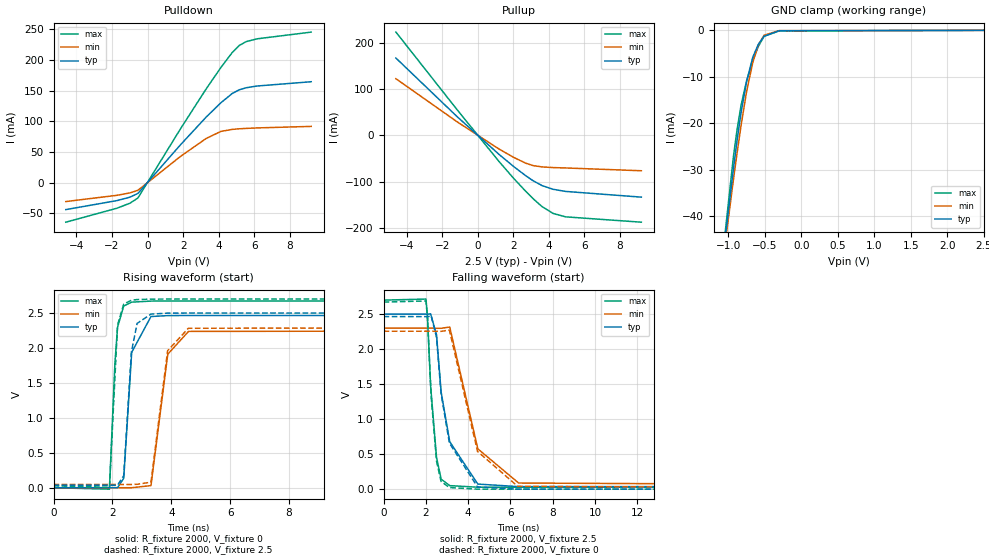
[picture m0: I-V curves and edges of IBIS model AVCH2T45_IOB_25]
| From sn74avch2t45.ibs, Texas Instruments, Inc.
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[Model]   AVCH2T45_IOB_25
Model_type  I/O
Vinl=0.7
Vinh=1.6
Enable   Active-High
Vref =   0
Rref =   2000
Cref =   15p
Vmeas =   1.25
| variable   typ   min   max
C_comp   5.05pF   4.26pF   5.75pF
| C_pullup   4.25pF   3.21pF   5.63pF
| C_pulldown   4.37pF   3.83pF   4.80pF
| C_tri-state   5.05pF   4.26pF   5.75pF
[Temperature Range]   40   100   -40
| Ambient temperature   25   85   -40
[Voltage range]   2.5   2.3   2.7
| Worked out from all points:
|   slope of the pulldown table from 0 to 0.375 V, typ, clamps not added: 29.4 ohm
|   slope of the pullup table from 0 to 0.375 V, typ, clamps not added: 28.8 ohm
|   GND clamp passes 1 mA (typ) near -0.49 V on its own axis
|   rising waveform, R_fixture 2000, V_fixture 0: 20-80 % time 216ps typ, 349ps min, 155ps max; typ from 0 V to 2.46 V
|   falling waveform, R_fixture 2000, V_fixture 2.5: 20-80 % time 733ps typ, 1.05ns min, 341ps max; typ from 2.5 V to 0.036 V
|   rising waveform, R_fixture 2000, V_fixture 2.5: 20-80 % time 214ps typ, 345ps min, 155ps max; typ from 0.036 V to 2.5 V
|   falling waveform, R_fixture 2000, V_fixture 0: 20-80 % time 727ps typ, 1.05ns min, 333ps max; typ from 2.46 V to 0 V
[GND Clamp]
| AVCH2T45_IOB_25
|   Voltage   I(typ)   I(min)   I(max)
-4.6V     -599.7mA   -548.2mA   -664.8mA
-1.105V   -53.1mA    -53.46mA   -52.72mA
-1.08V    -49.64mA   -50.32mA   -48.82mA
-930mV    -29.72mA   -32.1mA    -27.1mA
-880mV    -23.65mA   -26.37mA   -21.29mA
-825mV    -17.62mA   -20.4mA    -16.07mA
-750mV    -11.02mA   -13.17mA   -10.85mA
-665mV    -5.769mA   -6.898mA   -6.554mA
-590mV    -3.043mA   -3.142mA   -3.475mA
-510mV    -1.266mA   -1.045mA   -1.273mA
-305mV    -86.62uA   -60.85uA   -133.1uA
2.5V      1.213nA    2.547uA    -2.967uA
[Pulldown]
| AVCH2T45_IOB_25
|   Voltage   I(typ)   I(min)   I(max)
-4.6V     -43.76mA   -30.71mA   -64.27mA
-1.715V   -29.08mA   -20.46mA   -41.45mA
-985mV    -23.44mA   -16.53mA   -33.24mA
-545mV    -17.41mA   -12.35mA   -24.86mA
1.85V     61.76mA    42.85mA    87.78mA
3.295V    106.9mA    72.08mA    152.8mA
4.12V     130.1mA    83.49mA    187.5mA
4.755V    145.2mA    86.77mA    211.8mA
5.15V     151.2mA    87.75mA    223.4mA
5.545V    154.6mA    88.42mA    229.7mA
6.15V     157.4mA    89.19mA    234.2mA
9.2V      164.4mA    91.67mA    245.2mA
[Pullup]
| AVCH2T45_IOB_25
|   Voltage   I(typ)   I(min)   I(max)
-4.6V     167.2mA    122.6mA    223.3mA
-1.155V   40.55mA    29.45mA    55.44mA
1.195V    -40.71mA   -29.18mA   -56.05mA
2.025V    -67.14mA   -47.36mA   -92.77mA
2.695V    -86.73mA   -59.71mA   -120.4mA
3.12V     -97.9mA    -65.07mA   -136.7mA
3.615V    -108.1mA   -67.81mA   -153.5mA
4.245V    -116.2mA   -69.29mA   -168.4mA
4.95V     -120.8mA   -70.1mA    -175.7mA
9.2V      -133.1mA   -76.13mA   -187.2mA
[Ramp]
| AVCH2T45_IOB_25
| variable   typ   min   max
dV/dt_r   1.50/2.21E-10   1.38/3.60E-10   1.62/1.57E-10
dV/dt_f   1.49/7.36E-10   1.36/1.05E-09   1.62/3.43E-10
R_load = 2000
[Rising Waveform]
| AVCH2T45_IOB_25
R_fixture =   2000
C_fixture =   0
L_fixture =   0
V_fixture =   0
V_fixture_min = 0
V_fixture_max = 0
|   Time   V(typ)   V(min)   V(max)
0s        27.64nV    106.3nV    1.086nV
1.9ns     24.65uV    -1.302uV   -20.6mV
2.085ns   1.641mV    -40.27uV   1.785V
2.175ns   99.86uV    -22.47uV   2.297V
2.385ns   136mV      35.35uV    2.601V
2.655ns   1.938V     -145.3uV   2.656V
3.31ns    2.45V      30.54mV    2.671V
3.88ns    2.463V     1.911V     2.672V
4.585ns   2.465V     2.237V     2.672V
34.99ns   2.465V     2.256V     2.672V
[Falling Waveform]
| AVCH2T45_IOB_25
R_fixture =   2000
C_fixture =   0
L_fixture =   0
V_fixture =   2.5
V_fixture_min = 2.3
V_fixture_max = 2.7
|   Time   V(typ)   V(min)   V(max)
0s        2.5V       2.3V       2.7V
2ns       2.499V     2.3V       2.715V
2.07ns    2.498V     2.3V       2.487V
2.22ns    2.504V     2.3V       1.481V
2.5ns     2.206V     2.298V     455mV
2.72ns    1.385V     2.298V     142.7mV
3.125ns   678.5mV    2.315V     50.67mV
4.455ns   72.58mV    575.6mV    27.78mV
6.385ns   36.39mV    87.69mV    27.4mV
34.99ns   35.81mV    46.58mV    27.39mV
[Rising Waveform]
| AVCH2T45_IOB_25
R_fixture =   2000
C_fixture =   0
L_fixture =   0
V_fixture =   2.5
V_fixture_min = 2.3
V_fixture_max = 2.7
|   Time   V(typ)   V(min)   V(max)
0s        35.81mV    46.58mV    27.38mV
1.9ns     35.84mV    46.58mV    6.805mV
2.175ns   35.89mV    46.56mV    2.328V
2.385ns   173.2mV    46.62mV    2.629V
2.645ns   1.943V     46.4mV     2.683V
2.84ns    2.352V     49.48mV    2.693V
3.31ns    2.485V     78.76mV    2.699V
3.875ns   2.498V     1.961V     2.7V
4.58ns    2.5V       2.282V     2.7V
34.99ns   2.5V       2.3V       2.7V
[Falling Waveform]
| AVCH2T45_IOB_25
R_fixture =   2000
C_fixture =   0
L_fixture =   0
V_fixture =   0
V_fixture_min = 0
V_fixture_max = 0
|   Time   V(typ)   V(min)   V(max)
0s        2.465V     2.256V     2.672V
2ns       2.464V     2.256V     2.688V
2.07ns    2.462V     2.256V     2.46V
2.25ns    2.474V     2.256V     1.318V
2.5ns     2.17V      2.254V     403.8mV
2.715ns   1.367V     2.254V     110.3mV
3.11ns    659.2mV    2.272V     22.92mV
4.44ns    31.76mV    539.3mV    379.1uV
6.34ns    510.6uV    40.77mV    14.64uV
34.99ns   702.3nV    341.5nV    374.2nV
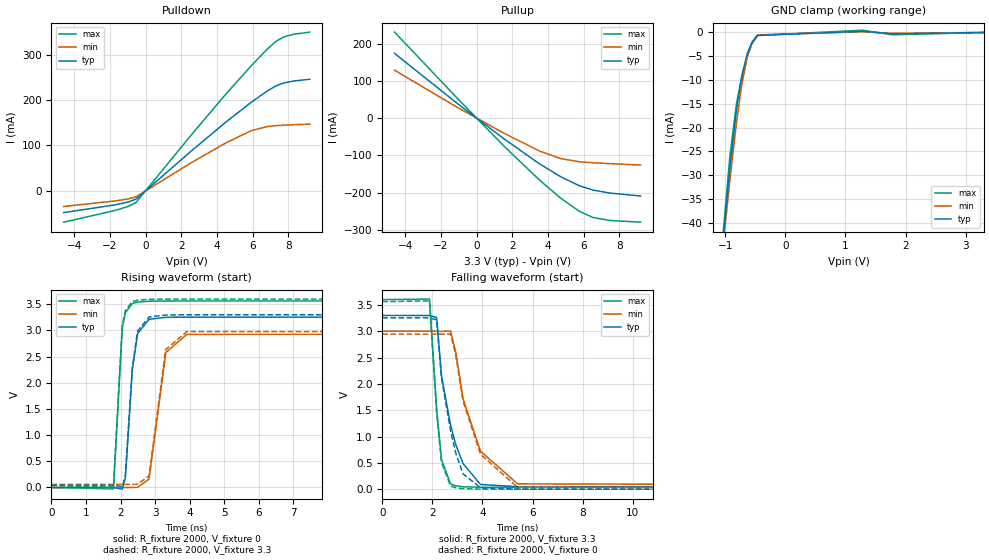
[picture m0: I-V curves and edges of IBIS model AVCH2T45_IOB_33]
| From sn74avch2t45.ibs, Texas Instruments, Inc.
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[Model]   AVCH2T45_IOB_33
Model_type  I/O
Vinl=0.8
Vinh=2.0
Enable   Active-High
Vref =   0
Rref =   2000
Cref =   15p
Vmeas =   1.65
| variable   typ   min   max
C_comp   4.94pF   3.97pF   5.93pF
| C_pullup   3.99pF   3.01pF   5.23pF
| C_pulldown   4.19pF   3.64pF   4.72pF
| C_tri-state   4.94pF   3.97pF   5.93pF
[Temperature Range]   40   100   -40
| Ambient temperature   25   85   -40
[Voltage range]   3.3   3   3.6
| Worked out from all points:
|   slope of the pulldown table from 0 to 0.495 V, typ, clamps not added: 28.7 ohm
|   slope of the pullup table from 0 to 0.495 V, typ, clamps not added: 27.4 ohm
|   GND clamp passes 1 mA (typ) near -0.49 V on its own axis
|   rising waveform, R_fixture 2000, V_fixture 0: 20-80 % time 203ps typ, 310ps min, 144ps max; typ from 0 V to 3.26 V
|   falling waveform, R_fixture 2000, V_fixture 3.3: 20-80 % time 749ps typ, 1.01ns min, 331ps max; typ from 3.3 V to 0.046 V
|   rising waveform, R_fixture 2000, V_fixture 3.3: 20-80 % time 202ps typ, 308ps min, 142ps max; typ from 0.046 V to 3.3 V
|   falling waveform, R_fixture 2000, V_fixture 0: 20-80 % time 666ps typ, 1.01ns min, 326ps max; typ from 3.26 V to 0 V
[GND Clamp]
| AVCH2T45_IOB_33
|   Voltage   I(typ)   I(min)   I(max)
-4.6V     -599.7mA   -548.3mA   -664.9mA
-1.12V    -55.23mA   -55.37mA   -55.14mA
-1.09V    -51.05mA   -51.59mA   -50.43mA
-920mV    -28.51mA   -30.95mA   -25.9mA
-810mV    -16.17mA   -18.87mA   -14.9mA
-725mV    -9.266mA   -11.11mA   -9.544mA
-630mV    -4.345mA   -4.957mA   -5.066mA
-555mV    -2.184mA   -2.008mA   -2.394mA
-460mV    -638.5uA   -501uA     -616.7uA
1.285V    253.4uA    145.8uA    464.3uA
1.78V     -297.7uA   -185uA     -481uA
3.3V      1.647nA    4.601uA    -26.77uA
[Pulldown]
| AVCH2T45_IOB_33
|   Voltage   I(typ)   I(min)   I(max)
-4.6V     -47.48mA   -33.99mA   -68.59mA
-1.68V    -30.25mA   -21.7mA    -42.42mA
-975mV    -24.15mA   -17.32mA   -33.81mA
-545mV    -17.86mA   -12.84mA   -25.24mA
2.545V    87.52mA    61.96mA    122.8mA
4.505V    151.8mA    106mA      213.5mA
5.905V    194.7mA    132.4mA    274.8mA
6.805V    219.6mA    141.6mA    311.5mA
7.315V    231.2mA    143.7mA    329.3mA
7.73V     237.3mA    144.7mA    338.5mA
8.28V     241.7mA    145.7mA    344.4mA
9.2V      245.6mA    146.9mA    349.3mA
[Pullup]
| AVCH2T45_IOB_33
|   Voltage   I(typ)   I(min)   I(max)
-4.6V     174.2mA    129.1mA    231.4mA
-1.105V   40.58mA    29.86mA    54.82mA
1.575V    -56.66mA   -41.45mA   -76.65mA
3.53V     -122.6mA   -88.07mA   -166.1mA
4.725V    -157.4mA   -108.5mA   -215.1mA
5.775V    -181.6mA   -117mA     -250.3mA
6.525V    -192.9mA   -119.7mA   -266.7mA
7.455V    -200.9mA   -121.9mA   -274.6mA
9.2V      -209mA     -126mA     -279.3mA
[Ramp]
| AVCH2T45_IOB_33
| variable   typ   min   max
dV/dt_r   1.98/2.08E-10   1.79/3.16E-10   2.16/1.47E-10
dV/dt_f   1.97/7.50E-10   1.78/1.01E-09   2.15/3.32E-10
R_load = 2000
[Rising Waveform]
| AVCH2T45_IOB_33
R_fixture =   2000
C_fixture =   0
L_fixture =   0
V_fixture =   0
V_fixture_min = 0
V_fixture_max = 0
|   Time   V(typ)   V(min)   V(max)
0s        37.78nV    120nV      1.948nV
1.795ns   -41.62uV   -5.564uV   -26.49mV
2.05ns    -31.95mV   31.85uV    3.053V
2.14ns    186.9mV    34.33uV    3.339V
2.34ns    2.241V     213.3uV    3.515V
2.495ns   2.943V     4.37mV     3.543V
2.825ns   3.214V     161.2mV    3.559V
3.31ns    3.251V     2.579V     3.563V
3.915ns   3.255V     2.924V     3.564V
34.99ns   3.256V     2.946V     3.564V
[Falling Waveform]
| AVCH2T45_IOB_33
R_fixture =   2000
C_fixture =   0
L_fixture =   0
V_fixture =   3.3
V_fixture_min = 3
V_fixture_max = 3.6
|   Time   V(typ)   V(min)   V(max)
0s        3.3V       3V         3.6V
1.885ns   3.299V     3V         3.611V
2.17ns    3.26V      2.999V     1.516V
2.365ns   2.151V     2.997V     563mV
2.725ns   1.225V     3.003V     99.44mV
2.93ns    851mV      2.613V     63.75mV
3.225ns   485.8mV    1.715V     45.39mV
3.92ns    89.79mV    720.9mV    36.9mV
5.4ns     47.02mV    101.4mV    35.99mV
34.99ns   46.09mV    58.43mV    35.95mV
[Rising Waveform]
| AVCH2T45_IOB_33
R_fixture =   2000
C_fixture =   0
L_fixture =   0
V_fixture =   3.3
V_fixture_min = 3
V_fixture_max = 3.6
|   Time   V(typ)   V(min)   V(max)
0s        46.09mV    58.43mV    35.95mV
1.795ns   46.05mV    58.42mV    9.38mV
2.05ns    14.01mV    58.46mV    3.1V
2.14ns    234mV      58.46mV    3.381V
2.34ns    2.293V     58.64mV    3.552V
2.495ns   2.992V     62.81mV    3.579V
2.825ns   3.259V     222mV      3.595V
3.305ns   3.295V     2.633V     3.599V
3.915ns   3.3V       2.978V     3.6V
34.99ns   3.3V       3V         3.6V
[Falling Waveform]
| AVCH2T45_IOB_33
R_fixture =   2000
C_fixture =   0
L_fixture =   0
V_fixture =   0
V_fixture_min = 0
V_fixture_max = 0
|   Time   V(typ)   V(min)   V(max)
0s        3.256V     2.946V     3.564V
1.885ns   3.254V     2.946V     3.575V
2.17ns    3.216V     2.945V     1.475V
2.365ns   2.112V     2.942V     508.9mV
2.725ns   1.111V     2.949V     61.96mV
2.935ns   686.6mV    2.542V     26.35mV
3.22ns    293.7mV    1.68V      9.24mV
3.92ns    26.15mV    662.8mV    910.3uV
5.385ns   561.1uV    41.65mV    33.46uV
34.99ns   797.6nV    736.7nV    341.7nV
